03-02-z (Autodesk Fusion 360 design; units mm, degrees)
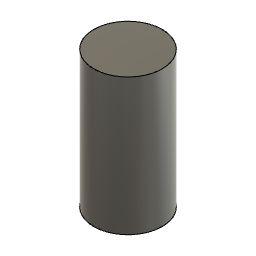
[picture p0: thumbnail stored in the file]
cylinder_primitive "円柱プリミティブ" Height 100 Diameter 50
